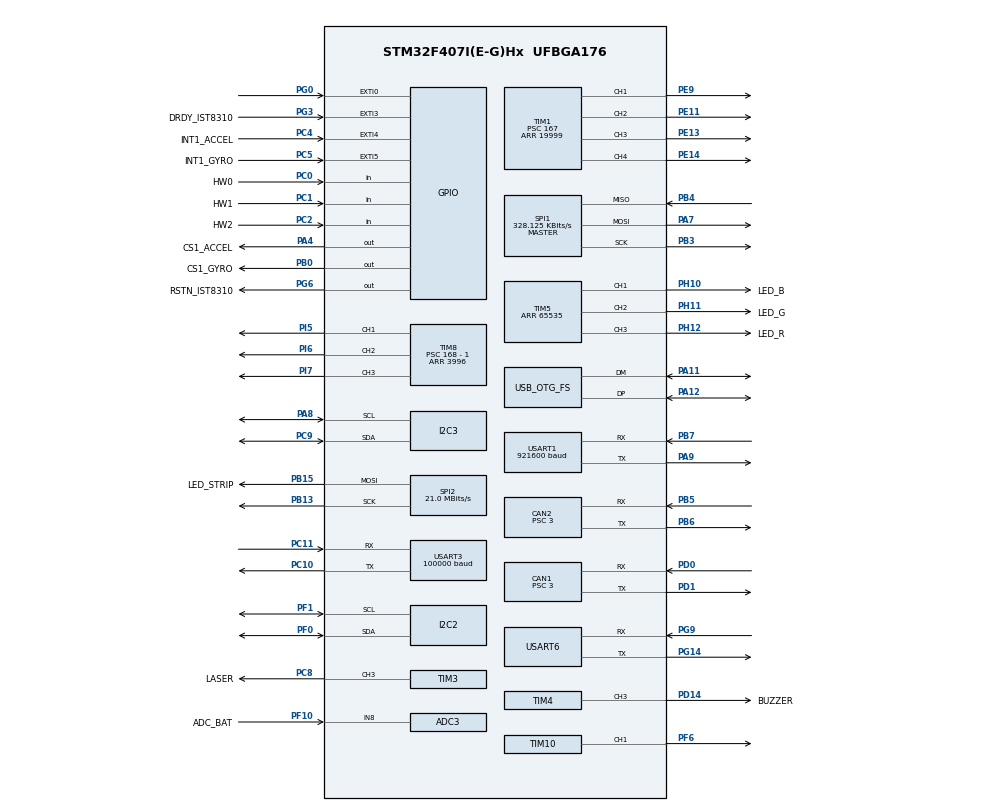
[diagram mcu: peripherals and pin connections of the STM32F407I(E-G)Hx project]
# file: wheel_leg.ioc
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ADC1.Channel-0\#ChannelRegularConversion=ADC_CHANNEL_TEMPSENSOR
ADC1.ClockPrescaler=ADC_CLOCK_SYNC_PCLK_DIV6
ADC1.NbrOfConversionFlag=1
ADC1.Rank-0\#ChannelRegularConversion=1
ADC1.SamplingTime-0\#ChannelRegularConversion=ADC_SAMPLETIME_3CYCLES
ADC1.master=1
ADC3.Channel-0\#ChannelRegularConversion=ADC_CHANNEL_8
ADC3.ClockPrescaler=ADC_CLOCK_SYNC_PCLK_DIV6
ADC3.NbrOfConversionFlag=1
ADC3.Rank-0\#ChannelRegularConversion=1
ADC3.SamplingTime-0\#ChannelRegularConversion=ADC_SAMPLETIME_3CYCLES
CAN1.ABOM=ENABLE
CAN1.BS1=CAN_BS1_10TQ
CAN1.BS2=CAN_BS2_3TQ
CAN1.CalculateBaudRate=1000000
CAN1.CalculateTimeBit=1000
CAN1.CalculateTimeQuantum=71.42857142857143
CAN1.NART=ENABLE
CAN1.Prescaler=3
CAN2.ABOM=ENABLE
CAN2.BS1=CAN_BS1_10TQ
CAN2.BS2=CAN_BS2_3TQ
CAN2.CalculateBaudRate=1000000
CAN2.CalculateTimeBit=1000
CAN2.CalculateTimeQuantum=71.42857142857143
CAN2.NART=ENABLE
CAN2.Prescaler=3
Dma.Request0=USART3_RX
Dma.Request1=SPI1_RX
Dma.Request2=SPI1_TX
Dma.Request3=SPI2_TX
Dma.Request4=USART1_RX
Dma.Request5=USART6_RX
Dma.Request6=USART6_TX
Dma.Request7=USART1_TX
Dma.SPI1_RX.1.Direction=DMA_PERIPH_TO_MEMORY
Dma.SPI1_RX.1.FIFOMode=DMA_FIFOMODE_DISABLE
Dma.SPI1_RX.1.Instance=DMA2_Stream2
Dma.SPI1_RX.1.MemDataAlignment=DMA_MDATAALIGN_BYTE
Dma.SPI1_RX.1.MemInc=DMA_MINC_ENABLE
Dma.SPI1_RX.1.Mode=DMA_NORMAL
Dma.SPI1_RX.1.PeriphDataAlignment=DMA_PDATAALIGN_BYTE
Dma.SPI1_RX.1.PeriphInc=DMA_PINC_DISABLE
Dma.SPI1_RX.1.Priority=DMA_PRIORITY_VERY_HIGH
Dma.SPI1_TX.2.Direction=DMA_MEMORY_TO_PERIPH
Dma.SPI1_TX.2.FIFOMode=DMA_FIFOMODE_DISABLE
Dma.SPI1_TX.2.Instance=DMA2_Stream3
Dma.SPI1_TX.2.MemDataAlignment=DMA_MDATAALIGN_BYTE
Dma.SPI1_TX.2.MemInc=DMA_MINC_ENABLE
Dma.SPI1_TX.2.Mode=DMA_NORMAL
Dma.SPI1_TX.2.PeriphDataAlignment=DMA_PDATAALIGN_BYTE
Dma.SPI1_TX.2.PeriphInc=DMA_PINC_DISABLE
Dma.SPI1_TX.2.Priority=DMA_PRIORITY_HIGH
Dma.SPI2_TX.3.Direction=DMA_MEMORY_TO_PERIPH
Dma.SPI2_TX.3.FIFOMode=DMA_FIFOMODE_DISABLE
Dma.SPI2_TX.3.Instance=DMA1_Stream4
Dma.SPI2_TX.3.MemDataAlignment=DMA_MDATAALIGN_BYTE
Dma.SPI2_TX.3.MemInc=DMA_MINC_ENABLE
Dma.SPI2_TX.3.Mode=DMA_NORMAL
Dma.SPI2_TX.3.PeriphDataAlignment=DMA_PDATAALIGN_BYTE
Dma.SPI2_TX.3.PeriphInc=DMA_PINC_DISABLE
Dma.SPI2_TX.3.Priority=DMA_PRIORITY_LOW
Dma.USART1_RX.4.Direction=DMA_PERIPH_TO_MEMORY
Dma.USART1_RX.4.FIFOMode=DMA_FIFOMODE_DISABLE
Dma.USART1_RX.4.Instance=DMA2_Stream5
Dma.USART1_RX.4.MemDataAlignment=DMA_MDATAALIGN_BYTE
Dma.USART1_RX.4.MemInc=DMA_MINC_ENABLE
Dma.USART1_RX.4.Mode=DMA_NORMAL
Dma.USART1_RX.4.PeriphDataAlignment=DMA_PDATAALIGN_BYTE
Dma.USART1_RX.4.PeriphInc=DMA_PINC_DISABLE
Dma.USART1_RX.4.Priority=DMA_PRIORITY_HIGH
Dma.USART1_TX.7.Direction=DMA_MEMORY_TO_PERIPH
Dma.USART1_TX.7.FIFOMode=DMA_FIFOMODE_DISABLE
Dma.USART1_TX.7.Instance=DMA2_Stream7
Dma.USART1_TX.7.MemDataAlignment=DMA_MDATAALIGN_BYTE
Dma.USART1_TX.7.MemInc=DMA_MINC_ENABLE
Dma.USART1_TX.7.Mode=DMA_NORMAL
Dma.USART1_TX.7.PeriphDataAlignment=DMA_PDATAALIGN_BYTE
Dma.USART1_TX.7.PeriphInc=DMA_PINC_DISABLE
Dma.USART1_TX.7.Priority=DMA_PRIORITY_MEDIUM
Dma.USART3_RX.0.Direction=DMA_PERIPH_TO_MEMORY
Dma.USART3_RX.0.FIFOMode=DMA_FIFOMODE_DISABLE
Dma.USART3_RX.0.Instance=DMA1_Stream1
Dma.USART3_RX.0.MemDataAlignment=DMA_MDATAALIGN_BYTE
Dma.USART3_RX.0.MemInc=DMA_MINC_ENABLE
Dma.USART3_RX.0.Mode=DMA_NORMAL
Dma.USART3_RX.0.PeriphDataAlignment=DMA_PDATAALIGN_BYTE
Dma.USART3_RX.0.PeriphInc=DMA_PINC_DISABLE
Dma.USART3_RX.0.Priority=DMA_PRIORITY_HIGH
Dma.USART6_RX.5.Direction=DMA_PERIPH_TO_MEMORY
Dma.USART6_RX.5.FIFOMode=DMA_FIFOMODE_ENABLE
Dma.USART6_RX.5.FIFOThreshold=DMA_FIFO_THRESHOLD_FULL
Dma.USART6_RX.5.Instance=DMA2_Stream1
Dma.USART6_RX.5.MemBurst=DMA_MBURST_SINGLE
Dma.USART6_RX.5.MemDataAlignment=DMA_MDATAALIGN_BYTE
Dma.USART6_RX.5.MemInc=DMA_MINC_ENABLE
Dma.USART6_RX.5.Mode=DMA_NORMAL
Dma.USART6_RX.5.PeriphBurst=DMA_PBURST_SINGLE
Dma.USART6_RX.5.PeriphDataAlignment=DMA_PDATAALIGN_BYTE
Dma.USART6_RX.5.PeriphInc=DMA_PINC_DISABLE
Dma.USART6_RX.5.Priority=DMA_PRIORITY_HIGH
Dma.USART6_TX.6.Direction=DMA_MEMORY_TO_PERIPH
Dma.USART6_TX.6.FIFOMode=DMA_FIFOMODE_DISABLE
Dma.USART6_TX.6.Instance=DMA2_Stream6
Dma.USART6_TX.6.MemDataAlignment=DMA_MDATAALIGN_BYTE
Dma.USART6_TX.6.MemInc=DMA_MINC_ENABLE
Dma.USART6_TX.6.Mode=DMA_NORMAL
Dma.USART6_TX.6.PeriphDataAlignment=DMA_PDATAALIGN_BYTE
Dma.USART6_TX.6.PeriphInc=DMA_PINC_DISABLE
Dma.USART6_TX.6.Priority=DMA_PRIORITY_MEDIUM
FREERTOS.INCLUDE_eTaskGetState=1
FREERTOS.INCLUDE_pcTaskGetTaskName=1
FREERTOS.INCLUDE_uxTaskGetStackHighWaterMark=1
FREERTOS.INCLUDE_uxTaskGetStackHighWaterMark2=0
FREERTOS.INCLUDE_vTaskCleanUpResources=1
FREERTOS.INCLUDE_vTaskDelayUntil=1
FREERTOS.INCLUDE_xEventGroupSetBitFromISR=1
FREERTOS.INCLUDE_xQueueGetMutexHolder=1
FREERTOS.INCLUDE_xSemaphoreGetMutexHolder=1
FREERTOS.INCLUDE_xTaskAbortDelay=1
FREERTOS.INCLUDE_xTaskGetCurrentTaskHandle=1
FREERTOS.INCLUDE_xTaskGetHandle=1
FREERTOS.INCLUDE_xTimerPendFunctionCall=1
FREERTOS.Tasks01=defaultTask,0,128,StartDefaultTask,Default,NULL,Dynamic,NULL,NULL
FREERTOS.configENABLE_FPU=1
FREERTOS.configGENERATE_RUN_TIME_STATS=0
FREERTOS.configTOTAL_HEAP_SIZE=24576
FREERTOS.configUSE_NEWLIB_REENTRANT=1
FREERTOS.configUSE_TIMERS=1
I2C3.I2C_Mode=I2C_Fast
Mcu.Family=STM32F4
Mcu.Name=STM32F407I(E-G)Hx
Mcu.Package=UFBGA176
NVIC.CAN1_RX0_IRQn=true\:5\:0\:false\:false\:true\:true\:true\:true\:true
NVIC.CAN1_RX1_IRQn=true\:5\:0\:false\:false\:true\:true\:true\:true\:true
NVIC.CAN1_TX_IRQn=true\:5\:0\:false\:false\:true\:true\:true\:true\:true
NVIC.CAN2_RX0_IRQn=true\:5\:0\:false\:false\:true\:true\:true\:true\:true
NVIC.CAN2_TX_IRQn=true\:5\:0\:false\:false\:true\:true\:true\:true\:true
NVIC.DMA1_Stream1_IRQn=true\:5\:0\:false\:false\:true\:true\:false\:true\:true
NVIC.DMA1_Stream4_IRQn=true\:5\:0\:false\:false\:true\:true\:false\:true\:true
NVIC.DMA2_Stream1_IRQn=true\:5\:0\:false\:false\:true\:true\:false\:true\:true
NVIC.DMA2_Stream2_IRQn=true\:5\:0\:false\:false\:true\:false\:false\:true\:true
NVIC.DMA2_Stream3_IRQn=true\:5\:0\:false\:false\:true\:true\:false\:true\:true
NVIC.DMA2_Stream5_IRQn=true\:5\:0\:false\:false\:true\:true\:false\:true\:true
NVIC.DMA2_Stream6_IRQn=true\:5\:0\:false\:false\:true\:true\:false\:true\:true
NVIC.DMA2_Stream7_IRQn=true\:5\:0\:false\:false\:true\:true\:false\:true\:true
NVIC.EXTI0_IRQn=true\:5\:0\:false\:false\:true\:true\:true\:true\:true
NVIC.EXTI3_IRQn=true\:5\:0\:false\:false\:true\:true\:true\:true\:true
NVIC.EXTI4_IRQn=true\:5\:0\:false\:false\:true\:true\:true\:true\:true
NVIC.EXTI9_5_IRQn=true\:5\:0\:false\:false\:true\:false\:true\:true\:true
NVIC.OTG_FS_IRQn=true\:5\:0\:false\:false\:true\:true\:false\:true\:true
NVIC.PriorityGroup=NVIC_PRIORITYGROUP_4
NVIC.TIM2_IRQn=true\:15\:0\:false\:false\:true\:false\:false\:true\:true
NVIC.TimeBase=TIM2_IRQn
NVIC.TimeBaseIP=TIM2
NVIC.USART1_IRQn=true\:5\:0\:false\:false\:true\:true\:true\:true\:true
NVIC.USART3_IRQn=true\:5\:0\:false\:false\:false\:true\:true\:true\:true
NVIC.USART6_IRQn=true\:5\:0\:false\:false\:true\:true\:true\:true\:true
PA11.Mode=Device_Only
PA11.Signal=USB_OTG_FS_DM
PA12.Mode=Device_Only
PA12.Signal=USB_OTG_FS_DP
PA13.Mode=Serial_Wire
PA13.Signal=SYS_JTMS-SWDIO
PA14.Mode=Serial_Wire
PA14.Signal=SYS_JTCK-SWCLK
PA4.GPIO_Label=CS1_ACCEL
PA4.GPIO_PuPd=GPIO_PULLUP
PA4.GPIO_Speed=GPIO_SPEED_FREQ_HIGH
PA4.PinState=GPIO_PIN_SET
PA4.Signal=GPIO_Output
PA7.GPIO_PuPd=GPIO_PULLUP
PA7.Mode=Full_Duplex_Master
PA7.Signal=SPI1_MOSI
PA8.Mode=I2C
PA8.Signal=I2C3_SCL
PA9.Mode=Asynchronous
PA9.Signal=USART1_TX
PB0.GPIO_Label=CS1_GYRO
PB0.GPIO_PuPd=GPIO_PULLUP
PB0.GPIO_Speed=GPIO_SPEED_FREQ_HIGH
PB0.PinState=GPIO_PIN_SET
PB0.Signal=GPIO_Output
PB13.Mode=TX_Only_Simplex_Unidirect_Master
PB13.Signal=SPI2_SCK
PB15.GPIO_Label=LED_STRIP
PB15.Mode=TX_Only_Simplex_Unidirect_Master
PB15.Signal=SPI2_MOSI
PB3.GPIO_PuPd=GPIO_PULLUP
PB3.Mode=Full_Duplex_Master
PB3.Signal=SPI1_SCK
PB4.GPIO_PuPd=GPIO_PULLUP
PB4.Mode=Full_Duplex_Master
PB4.Signal=SPI1_MISO
PB5.Mode=CAN_Activate
PB5.Signal=CAN2_RX
PB6.Mode=CAN_Activate
PB6.Signal=CAN2_TX
PB7.Mode=Asynchronous
PB7.Signal=USART1_RX
PC0.GPIO_Label=HW0
PC0.Signal=GPIO_Input
PC1.GPIO_Label=HW1
PC1.Signal=GPIO_Input
PC10.Mode=Asynchronous
PC10.Signal=USART3_TX
PC11.Mode=Asynchronous
PC11.Signal=USART3_RX
PC2.GPIO_Label=HW2
PC2.Signal=GPIO_Input
PC4.GPIO_Label=INT1_ACCEL
PC4.GPIO_ModeDefaultEXTI=GPIO_MODE_IT_FALLING
PC4.GPIO_PuPd=GPIO_PULLUP
PC4.Signal=GPXTI4
PC5.GPIO_Label=INT1_GYRO
PC5.GPIO_ModeDefaultEXTI=GPIO_MODE_IT_FALLING
PC5.GPIO_PuPd=GPIO_PULLUP
PC5.Signal=GPXTI5
PC8.GPIO_Label=LASER
PC8.GPIO_PuPd=GPIO_PULLUP
PC8.GPIO_Speed=GPIO_SPEED_FREQ_HIGH
PC8.Signal=S_TIM3_CH3
PC9.Mode=I2C
PC9.Signal=I2C3_SDA
PD0.Mode=CAN_Activate
PD0.Signal=CAN1_RX
PD1.Mode=CAN_Activate
PD1.Signal=CAN1_TX
PD14.GPIO_Label=BUZZER
PD14.GPIO_PuPd=GPIO_PULLUP
PD14.GPIO_Speed=GPIO_SPEED_FREQ_VERY_HIGH
PD14.Signal=S_TIM4_CH3
PE11.Signal=S_TIM1_CH2
PE13.Signal=S_TIM1_CH3
PE14.Signal=S_TIM1_CH4
PE9.GPIO_PuPd=GPIO_PULLUP
PE9.GPIO_Speed=GPIO_SPEED_FREQ_HIGH
PE9.Signal=S_TIM1_CH1
PF0.Mode=I2C
PF0.Signal=I2C2_SDA
PF1.Mode=I2C
PF1.Signal=I2C2_SCL
PF10.GPIO_Label=ADC_BAT
PF10.Mode=IN8
PF10.Signal=ADC3_IN8
PF6.GPIO_ModeDefaultPP=GPIO_MODE_AF_PP
PF6.GPIO_PuPd=GPIO_PULLUP
PF6.GPIO_Speed=GPIO_SPEED_FREQ_HIGH
PF6.Signal=S_TIM10_CH1
PG0.GPIO_ModeDefaultEXTI=GPIO_MODE_IT_FALLING
PG0.GPIO_PuPd=GPIO_PULLUP
PG0.Signal=GPXTI0
PG14.Mode=Asynchronous
PG14.Signal=USART6_TX
PG3.GPIO_Label=DRDY_IST8310
PG3.GPIO_ModeDefaultEXTI=GPIO_MODE_IT_FALLING
PG3.GPIO_PuPd=GPIO_PULLUP
PG3.Signal=GPXTI3
PG6.GPIO_Label=RSTN_IST8310
PG6.GPIO_ModeDefaultOutputPP=GPIO_MODE_OUTPUT_PP
PG6.GPIO_PuPd=GPIO_PULLUP
PG6.GPIO_Speed=GPIO_SPEED_FREQ_MEDIUM
PG6.PinState=GPIO_PIN_SET
PG6.Signal=GPIO_Output
PG9.Mode=Asynchronous
PG9.Signal=USART6_RX
PH0-OSC_IN.Mode=HSE-External-Oscillator
PH0-OSC_IN.Signal=RCC_OSC_IN
PH1-OSC_OUT.Mode=HSE-External-Oscillator
PH1-OSC_OUT.Signal=RCC_OSC_OUT
PH10.GPIO_Label=LED_B
PH10.GPIO_PuPd=GPIO_PULLUP
PH10.GPIO_Speed=GPIO_SPEED_FREQ_HIGH
PH10.Signal=S_TIM5_CH1
PH11.GPIO_Label=LED_G
PH11.GPIO_PuPd=GPIO_PULLUP
PH11.GPIO_Speed=GPIO_SPEED_FREQ_HIGH
PH11.Signal=S_TIM5_CH2
PH12.GPIO_Label=LED_R
PH12.GPIO_PuPd=GPIO_PULLUP
PH12.GPIO_Speed=GPIO_SPEED_FREQ_HIGH
PH12.Signal=S_TIM5_CH3
PI5.Signal=S_TIM8_CH1
PI6.GPIO_PuPd=GPIO_PULLUP
PI6.GPIO_Speed=GPIO_SPEED_FREQ_VERY_HIGH
PI6.Signal=S_TIM8_CH2
PI7.GPIO_PuPd=GPIO_PULLUP
PI7.GPIO_Speed=GPIO_SPEED_FREQ_VERY_HIGH
PI7.Signal=S_TIM8_CH3
ProjectManager.HeapSize=0x1000
ProjectManager.StackSize=0x1000
ProjectManager.TargetToolchain=STM32CubeIDE
RCC.48MHZClocksFreq_Value=48000000
RCC.AHBFreq_Value=168000000
RCC.APB1CLKDivider=RCC_HCLK_DIV4
RCC.APB1Freq_Value=42000000
RCC.APB1TimFreq_Value=84000000
RCC.APB2CLKDivider=RCC_HCLK_DIV2
RCC.APB2Freq_Value=84000000
RCC.APB2TimFreq_Value=168000000
RCC.CortexFreq_Value=168000000
RCC.HCLKFreq_Value=168000000
RCC.HSE_VALUE=12000000
RCC.HSI_VALUE=16000000
RCC.LSE_VALUE=32768
RCC.PLLM=6
RCC.PLLN=168
RCC.PLLQ=7
RCC.SYSCLKFreq_VALUE=168000000
RCC.SYSCLKSource=RCC_SYSCLKSOURCE_PLLCLK
RCC.VCOOutputFreq_Value=336000000
SH.S_TIM10_CH1.0=TIM10_CH1,PWM Generation1 CH1
SH.S_TIM1_CH1.0=TIM1_CH1,PWM Generation1 CH1
SH.S_TIM1_CH2.0=TIM1_CH2,PWM Generation2 CH2
SH.S_TIM1_CH3.0=TIM1_CH3,PWM Generation3 CH3
SH.S_TIM1_CH4.0=TIM1_CH4,PWM Generation4 CH4
SH.S_TIM3_CH3.0=TIM3_CH3,PWM Generation3 CH3
SH.S_TIM4_CH3.0=TIM4_CH3,PWM Generation3 CH3
SH.S_TIM5_CH1.0=TIM5_CH1,PWM Generation1 CH1
SH.S_TIM5_CH2.0=TIM5_CH2,PWM Generation2 CH2
SH.S_TIM5_CH3.0=TIM5_CH3,PWM Generation3 CH3
SH.S_TIM8_CH1.0=TIM8_CH1,PWM Generation1 CH1
SH.S_TIM8_CH2.0=TIM8_CH2,PWM Generation2 CH2
SH.S_TIM8_CH3.0=TIM8_CH3,PWM Generation3 CH3
SPI1.BaudRatePrescaler=SPI_BAUDRATEPRESCALER_256
SPI1.CLKPhase=SPI_PHASE_2EDGE
SPI1.CLKPolarity=SPI_POLARITY_HIGH
SPI1.CalculateBaudRate=328.125 KBits/s
SPI1.Direction=SPI_DIRECTION_2LINES
SPI1.Mode=SPI_MODE_MASTER
SPI1.VirtualType=VM_MASTER
SPI2.CalculateBaudRate=21.0 MBits/s
SPI2.Direction=SPI_DIRECTION_2LINES
SPI2.Mode=SPI_MODE_MASTER
SPI2.VirtualType=VM_MASTER
STMicroelectronics.X-CUBE-ALGOBUILD.1.3.0.LibraryCcDSPOoLibraryJjDSPOoLibrary=true
TIM1.Channel-PWM\ Generation1\ CH1=TIM_CHANNEL_1
TIM1.Channel-PWM\ Generation2\ CH2=TIM_CHANNEL_2
TIM1.Channel-PWM\ Generation3\ CH3=TIM_CHANNEL_3
TIM1.Channel-PWM\ Generation4\ CH4=TIM_CHANNEL_4
TIM1.Period=19999
TIM1.Prescaler=167
TIM1.Pulse-PWM\ Generation1\ CH1=1000
TIM10.Channel=TIM_CHANNEL_1
TIM10.Period=4999
TIM3.Channel-PWM\ Generation3\ CH3=TIM_CHANNEL_3
TIM4.Channel-PWM\ Generation3\ CH3=TIM_CHANNEL_3
TIM4.Period=20999
TIM4.Prescaler=167
TIM5.Channel-PWM\ Generation1\ CH1=TIM_CHANNEL_1
TIM5.Channel-PWM\ Generation2\ CH2=TIM_CHANNEL_2
TIM5.Channel-PWM\ Generation3\ CH3=TIM_CHANNEL_3
TIM5.Period=65535
TIM8.AutoReloadPreload=TIM_AUTORELOAD_PRELOAD_ENABLE
TIM8.Channel-PWM\ Generation1\ CH1=TIM_CHANNEL_1
TIM8.Channel-PWM\ Generation2\ CH2=TIM_CHANNEL_2
TIM8.Channel-PWM\ Generation3\ CH3=TIM_CHANNEL_3
TIM8.Period=3996
TIM8.Prescaler=168 - 1
TIM8.Pulse-PWM\ Generation2\ CH2=1500
TIM8.Pulse-PWM\ Generation3\ CH3=1500
USART1.BaudRate=921600
USART1.Mode=MODE_TX_RX
USART1.Parity=PARITY_NONE
USART1.VirtualMode=VM_ASYNC
USART3.BaudRate=100000
USART3.Mode=MODE_RX
USART3.Parity=PARITY_EVEN
USART3.VirtualMode=VM_ASYNC
USART6.VirtualMode=VM_ASYNC
USB_DEVICE.CLASS_NAME_FS=CDC
USB_DEVICE.VirtualMode-CDC_FS=Cdc
USB_DEVICE.VirtualModeFS=Cdc_FS
USB_OTG_FS.VirtualMode=Device_Only
VP_ADC1_TempSens_Input.Mode=IN-TempSens
VP_ADC1_Vref_Input.Mode=IN-Vrefint
VP_CRC_VS_CRC.Mode=CRC_Activate
VP_FREERTOS_VS_CMSIS_V1.Mode=CMSIS_V1
VP_RNG_VS_RNG.Mode=RNG_Activate
VP_STMicroelectronics.X-CUBE-ALGOBUILD_VS_DSPOoLibraryJjLibrary_1.3.0_1.3.0.Mode=DSPOoLibraryJjLibrary
VP_SYS_VS_tim2.Mode=TIM2
VP_TIM10_VS_ClockSourceINT.Mode=Enable_Timer
VP_TIM4_VS_ClockSourceINT.Mode=Internal
VP_TIM5_VS_ClockSourceINT.Mode=Internal
VP_TIM8_VS_ClockSourceINT.Mode=Internal
VP_USB_DEVICE_VS_USB_DEVICE_CDC_FS.Mode=CDC_FS
board=custom

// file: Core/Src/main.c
/* USER CODE BEGIN Header */
/**
  ******************************************************************************
  * @file           : main.c
  * @brief          : Main program body
  ******************************************************************************
  * @attention
  *
  * Copyright (c) 2024 STMicroelectronics.
  * All rights reserved.
  *
  * This software is licensed under terms that can be found in the LICENSE file
  * in the root directory of this software component.
  * If no LICENSE file comes with this software, it is provided AS-IS.
  *
  ******************************************************************************
  */
/* USER CODE END Header */
#include "main.h"
#include "cmsis_os.h"
#include "adc.h"
#include "can.h"
#include "crc.h"
#include "dma.h"
#include "i2c.h"
#include "rng.h"
#include "spi.h"
#include "tim.h"
#include "usart.h"
#include "usb_device.h"
#include "gpio.h"

/* USER CODE BEGIN Includes */
#include "bsp_delay.h"
#include "bsp_can.h"
#include "remote.h"
#include "BMI088driver.h"
#include "buzzer.h"
#include "bsp_usart.h"
#include "../../User/App/Referee_Task/referee_task.h"
#include "calibrate_task.h"
/* USER CODE END Includes */

void SystemClock_Config(void);
void MX_FREERTOS_Init(void);

int main(void)
{

  /* MCU Configuration--------------------------------------------------------*/

  /* Reset of all peripherals, Initializes the Flash interface and the Systick. */
  HAL_Init();

  /* Configure the system clock */
  SystemClock_Config();

  /* Initialize all configured peripherals */
  MX_GPIO_Init();
  MX_DMA_Init();
  MX_USART3_UART_Init();
  MX_CAN1_Init();
  MX_CAN2_Init();
  MX_SPI1_Init();
  MX_I2C3_Init();
  MX_TIM4_Init();
  MX_TIM5_Init();
  MX_TIM10_Init();
  MX_I2C2_Init();
  MX_ADC1_Init();
  MX_ADC3_Init();
  MX_SPI2_Init();
  MX_TIM1_Init();
  MX_TIM3_Init();
  MX_TIM8_Init();
  MX_USART1_UART_Init();
  MX_USART6_UART_Init();
  MX_CRC_Init();
  MX_RNG_Init();
  /* USER CODE BEGIN 2 */
    delay_init();
    HAL_TIM_PWM_Start(&htim8,TIM_CHANNEL_1);
    HAL_TIM_PWM_Start(&htim8,TIM_CHANNEL_2);
    HAL_TIM_PWM_Start(&htim8,TIM_CHANNEL_3);
    HAL_TIM_Base_Start(&htim1);
    HAL_TIM_PWM_Start(&htim1,TIM_CHANNEL_1);
    HAL_TIM_PWM_Start(&htim1,TIM_CHANNEL_2);
    HAL_TIM_PWM_Start(&htim1,TIM_CHANNEL_3);
    HAL_TIM_PWM_Start(&htim1,TIM_CHANNEL_4);
    usart6_init(&usart6_buf[0], REFEREE_BUFFER_SIZE);
    usart1_init(&usart1_buf[0], REFEREE_BUFFER_SIZE);

    can_filter_init();

    cali_param_init();
    remote_control_init();
  /* USER CODE END 2 */

  /* Call init function for freertos objects (in freertos.c) */
  MX_FREERTOS_Init();

  /* Start scheduler */
  osKernelStart();

  /* We should never get here as control is now taken by the scheduler */
  /* Infinite loop */
  while (1)
  {

  }
}

void SystemClock_Config(void)
{
    RCC_OscInitTypeDef RCC_OscInitStruct = {0};
    RCC_ClkInitTypeDef RCC_ClkInitStruct = {0};

    /** Configure the main internal regulator output voltage
    */
    __HAL_RCC_PWR_CLK_ENABLE();
    __HAL_PWR_VOLTAGESCALING_CONFIG(PWR_REGULATOR_VOLTAGE_SCALE1);
    // 先将时钟源选择为内部时钟
    RCC_ClkInitStruct.ClockType = RCC_CLOCKTYPE_SYSCLK;
    RCC_ClkInitStruct.SYSCLKSource = RCC_SYSCLKSOURCE_HSI;
    if (HAL_RCC_ClockConfig(&RCC_ClkInitStruct, FLASH_LATENCY_5) != HAL_OK)
    {
        Error_Handler();
    }
    /** Initializes the RCC Oscillators according to the specified parameters
    * in the RCC_OscInitTypeDef structure.
    */
    RCC_OscInitStruct.OscillatorType = RCC_OSCILLATORTYPE_HSE;
    RCC_OscInitStruct.HSEState = RCC_HSE_ON;
    RCC_OscInitStruct.PLL.PLLState = RCC_PLL_ON;
    RCC_OscInitStruct.PLL.PLLSource = RCC_PLLSOURCE_HSE;
    RCC_OscInitStruct.PLL.PLLM = 6;
    RCC_OscInitStruct.PLL.PLLN = 168;
    RCC_OscInitStruct.PLL.PLLP = RCC_PLLP_DIV2;
    RCC_OscInitStruct.PLL.PLLQ = 7;
    if (HAL_RCC_OscConfig(&RCC_OscInitStruct) != HAL_OK)
    {
        Error_Handler();
    }

    /** Initializes the CPU, AHB and APB buses clocks
    */
    RCC_ClkInitStruct.ClockType = RCC_CLOCKTYPE_HCLK|RCC_CLOCKTYPE_SYSCLK
                                  |RCC_CLOCKTYPE_PCLK1|RCC_CLOCKTYPE_PCLK2;
    RCC_ClkInitStruct.SYSCLKSource = RCC_SYSCLKSOURCE_PLLCLK;
    RCC_ClkInitStruct.AHBCLKDivider = RCC_SYSCLK_DIV1;
    RCC_ClkInitStruct.APB1CLKDivider = RCC_HCLK_DIV4;
    RCC_ClkInitStruct.APB2CLKDivider = RCC_HCLK_DIV2;

    if (HAL_RCC_ClockConfig(&RCC_ClkInitStruct, FLASH_LATENCY_5) != HAL_OK)
    {
        Error_Handler();
    }
    // 禁用内部高速时钟
    RCC_OscInitStruct.OscillatorType = RCC_OSCILLATORTYPE_HSI;
    RCC_OscInitStruct.HSIState = RCC_HSI_OFF;
    RCC_OscInitStruct.PLL.PLLState = RCC_PLL_NONE;
    if(HAL_RCC_OscConfig(&RCC_OscInitStruct) != HAL_OK)
    {
        Error_Handler();
    }
}

void HAL_TIM_PeriodElapsedCallback(TIM_HandleTypeDef *htim)
{
  if (htim->Instance == TIM2) {
    HAL_IncTick();
  }
}

void Error_Handler(void)
{
  __disable_irq();
  while (1)
  {
  }
}

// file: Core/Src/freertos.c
/* USER CODE BEGIN Header */
/**
  ******************************************************************************
  * File Name          : freertos.c
  * Description        : Code for freertos applications
  ******************************************************************************
  * @attention
  *
  * Copyright (c) 2024 STMicroelectronics.
  * All rights reserved.
  *
  * This software is licensed under terms that can be found in the LICENSE file
  * in the root directory of this software component.
  * If no LICENSE file comes with this software, it is provided AS-IS.
  *
  ******************************************************************************
  */
/* USER CODE END Header */

#include "FreeRTOS.h"
#include "task.h"
#include "main.h"
#include "cmsis_os.h"

/* USER CODE BEGIN Includes */
#include "robot_def.h"
#include "buzzer.h"
#include "ins_task.h"
#include "gimbal_task.h"
#include "decode.h"
#include "usb_task.h"
/* USER CODE END Includes */

osThreadId defaultTaskHandle;

osThreadId calibrateTaskHandle;

osThreadId gimbalTaskHandle;
osThreadId imuTaskHandle;
osThreadId detectTaskHandle;
osThreadId usbtaskHandle;
osThreadId decodetaskHandle;

void StartDefaultTask(void const * argument);

extern void MX_USB_DEVICE_Init(void);
void MX_FREERTOS_Init(void); /* (MISRA C 2004 rule 8.1) */

/* GetIdleTaskMemory prototype (linked to static allocation support) */
void vApplicationGetIdleTaskMemory( StaticTask_t **ppxIdleTaskTCBBuffer, StackType_t **ppxIdleTaskStackBuffer, uint32_t *pulIdleTaskStackSize );

/* GetTimerTaskMemory prototype (linked to static allocation support) */
void vApplicationGetTimerTaskMemory( StaticTask_t **ppxTimerTaskTCBBuffer, StackType_t **ppxTimerTaskStackBuffer, uint32_t *pulTimerTaskStackSize );

/* USER CODE BEGIN GET_IDLE_TASK_MEMORY */
static StaticTask_t xIdleTaskTCBBuffer;
static StackType_t xIdleStack[configMINIMAL_STACK_SIZE];

void vApplicationGetIdleTaskMemory(StaticTask_t **ppxIdleTaskTCBBuffer,
                                   StackType_t **ppxIdleTaskStackBuffer,
                                   uint32_t *pulIdleTaskStackSize) {
  *ppxIdleTaskTCBBuffer = &xIdleTaskTCBBuffer;
  *ppxIdleTaskStackBuffer = &xIdleStack[0];
  *pulIdleTaskStackSize = configMINIMAL_STACK_SIZE;
  /* place for user code */
}

QueueHandle_t CDC_send_queue;

/* USER CODE END GET_IDLE_TASK_MEMORY */

/* USER CODE BEGIN GET_TIMER_TASK_MEMORY */
static StaticTask_t xTimerTaskTCBBuffer;
static StackType_t xTimerStack[configTIMER_TASK_STACK_DEPTH];

void vApplicationGetTimerTaskMemory(StaticTask_t **ppxTimerTaskTCBBuffer,
                                    StackType_t **ppxTimerTaskStackBuffer,
                                    uint32_t *pulTimerTaskStackSize) {
  *ppxTimerTaskTCBBuffer = &xTimerTaskTCBBuffer;
  *ppxTimerTaskStackBuffer = &xTimerStack[0];
  *pulTimerTaskStackSize = configTIMER_TASK_STACK_DEPTH;
  /* place for user code */
}
/* USER CODE END GET_TIMER_TASK_MEMORY */

void MX_FREERTOS_Init(void) {

  /* Create the thread(s) */
  /* definition and creation of defaultTask */
  osThreadDef(defaultTask, StartDefaultTask, osPriorityIdle, 0, 128);
  defaultTaskHandle = osThreadCreate(osThread(defaultTask), NULL);

    /* definition and creation of gimbalTask */
    osThreadDef(gimbalTask, Gimbal_task, osPriorityHigh, 0, 512);
    gimbalTaskHandle = osThreadCreate(osThread(gimbalTask), NULL);

    /* definition and creation of imuTask */
    osThreadDef(imuTask, INS_task, osPriorityIdle, 0, 512);
    imuTaskHandle = osThreadCreate(osThread(imuTask), NULL);

//    /* definition and creation of detectTask */
//    osThreadDef(detectTask, Detect_task, osPriorityIdle, 0, 128);
//    detectTaskHandle = osThreadCreate(osThread(detectTask), NULL);
//
//    /* definition and creation of usbtask */
//    osThreadDef(usbtask, USB_task, osPriorityHigh, 0, 128);
//    usbtaskHandle = osThreadCreate(osThread(usbtask), NULL);
//
//    /* definition and creation of decodetask */
//    osThreadDef(decodetask, Decode_task, osPriorityHigh, 0, 128);
//    decodetaskHandle = osThreadCreate(osThread(decodetask), NULL);

  /* USER CODE BEGIN RTOS_THREADS */

//    CDC_send_queue = xQueueCreate(1, 128);

  /* USER CODE END RTOS_THREADS */

}

void StartDefaultTask(void const * argument)
{
  /* init code for USB_DEVICE */
  MX_USB_DEVICE_Init();
  for (;;) {
    osDelay(1);
  }
}
